VERSION 5.7 ;
  NOWIREEXTENSIONATPIN ON ;
  DIVIDERCHAR "/" ;
  BUSBITCHARS "[]" ;
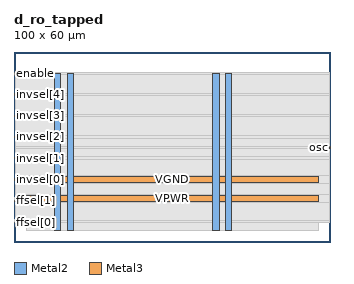
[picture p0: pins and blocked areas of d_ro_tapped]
MACRO d_ro_tapped
  CLASS BLOCK ;
  FOREIGN d_ro_tapped ;
  ORIGIN 0.000 0.000 ;
  SIZE 100.000 BY 60.000 ;
  PIN VGND
    DIRECTION INOUT ;
    USE GROUND ;
    PORT
      LAYER Metal2 ;
        RECT 16.840 3.560 18.840 53.140 ;
    END
    PORT
      LAYER Metal2 ;
        RECT 66.840 3.560 68.840 53.140 ;
    END
    PORT
      LAYER Metal3 ;
        RECT 3.840 18.780 96.000 20.780 ;
    END
  END VGND
  PIN VPWR
    DIRECTION INOUT ;
    USE POWER ;
    PORT
      LAYER Metal2 ;
        RECT 12.840 3.560 14.840 53.140 ;
    END
    PORT
      LAYER Metal2 ;
        RECT 62.840 3.560 64.840 53.140 ;
    END
    PORT
      LAYER Metal3 ;
        RECT 3.840 12.780 96.000 14.780 ;
    END
  END VPWR
  PIN enable
    DIRECTION INPUT ;
    USE SIGNAL ;
    ANTENNAGATEAREA 0.180700 ;
    PORT
      LAYER Metal3 ;
        RECT 0.000 53.140 0.400 53.540 ;
    END
  END enable
  PIN ffsel[0]
    DIRECTION INPUT ;
    USE SIGNAL ;
    ANTENNAGATEAREA 0.180700 ;
    PORT
      LAYER Metal3 ;
        RECT 0.000 6.100 0.400 6.500 ;
    END
  END ffsel[0]
  PIN ffsel[1]
    DIRECTION INPUT ;
    USE SIGNAL ;
    ANTENNAGATEAREA 0.180700 ;
    PORT
      LAYER Metal3 ;
        RECT 0.000 12.820 0.400 13.220 ;
    END
  END ffsel[1]
  PIN invsel[0]
    DIRECTION INPUT ;
    USE SIGNAL ;
    ANTENNAGATEAREA 0.180700 ;
    PORT
      LAYER Metal3 ;
        RECT 0.000 19.540 0.400 19.940 ;
    END
  END invsel[0]
  PIN invsel[1]
    DIRECTION INPUT ;
    USE SIGNAL ;
    ANTENNAGATEAREA 0.180700 ;
    PORT
      LAYER Metal3 ;
        RECT 0.000 26.260 0.400 26.660 ;
    END
  END invsel[1]
  PIN invsel[2]
    DIRECTION INPUT ;
    USE SIGNAL ;
    ANTENNAGATEAREA 0.180700 ;
    PORT
      LAYER Metal3 ;
        RECT 0.000 32.980 0.400 33.380 ;
    END
  END invsel[2]
  PIN invsel[3]
    DIRECTION INPUT ;
    USE SIGNAL ;
    ANTENNAGATEAREA 0.180700 ;
    PORT
      LAYER Metal3 ;
        RECT 0.000 39.700 0.400 40.100 ;
    END
  END invsel[3]
  PIN invsel[4]
    DIRECTION INPUT ;
    USE SIGNAL ;
    ANTENNAGATEAREA 0.180700 ;
    PORT
      LAYER Metal3 ;
        RECT 0.000 46.420 0.400 46.820 ;
    END
  END invsel[4]
  PIN osc
    DIRECTION OUTPUT ;
    USE SIGNAL ;
    ANTENNADIFFAREA 0.708600 ;
    PORT
      LAYER Metal3 ;
        RECT 99.600 29.620 100.000 30.020 ;
    END
  END osc
  OBS
      LAYER GatPoly ;
        RECT 3.840 3.630 96.000 53.070 ;
      LAYER Metal1 ;
        RECT 3.840 3.560 96.000 53.140 ;
      LAYER Metal2 ;
        RECT 3.255 53.350 95.625 53.485 ;
        RECT 3.255 6.155 12.630 53.350 ;
        RECT 15.050 6.155 16.630 53.350 ;
        RECT 19.050 6.155 62.630 53.350 ;
        RECT 65.050 6.155 66.630 53.350 ;
        RECT 69.050 6.155 95.625 53.350 ;
      LAYER Metal3 ;
        RECT 0.610 52.930 99.600 53.440 ;
        RECT 0.400 47.030 99.600 52.930 ;
        RECT 0.610 46.210 99.600 47.030 ;
        RECT 0.400 40.310 99.600 46.210 ;
        RECT 0.610 39.490 99.600 40.310 ;
        RECT 0.400 33.590 99.600 39.490 ;
        RECT 0.610 32.770 99.600 33.590 ;
        RECT 0.400 30.230 99.600 32.770 ;
        RECT 0.400 29.410 99.390 30.230 ;
        RECT 0.400 26.870 99.600 29.410 ;
        RECT 0.610 26.050 99.600 26.870 ;
        RECT 0.400 20.990 99.600 26.050 ;
        RECT 0.400 20.150 3.630 20.990 ;
        RECT 0.610 19.330 3.630 20.150 ;
        RECT 0.400 18.570 3.630 19.330 ;
        RECT 96.210 18.570 99.600 20.990 ;
        RECT 0.400 14.990 99.600 18.570 ;
        RECT 0.400 13.430 3.630 14.990 ;
        RECT 0.610 12.610 3.630 13.430 ;
        RECT 0.400 12.570 3.630 12.610 ;
        RECT 96.210 12.570 99.600 14.990 ;
        RECT 0.400 6.710 99.600 12.570 ;
        RECT 0.610 6.200 99.600 6.710 ;
  END
END d_ro_tapped
END LIBRARY

